VERSION 5.7 ;
BUSBITCHARS "[]" ;
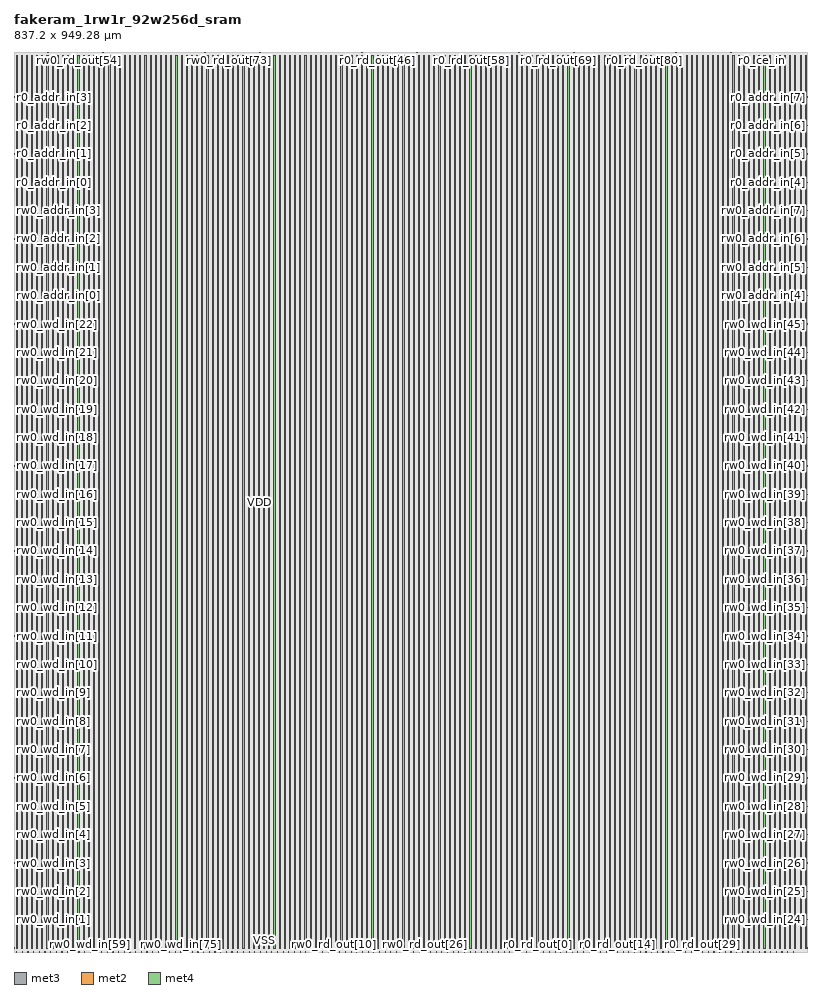
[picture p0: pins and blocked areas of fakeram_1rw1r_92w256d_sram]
MACRO fakeram_1rw1r_92w256d_sram
  FOREIGN fakeram_1rw1r_92w256d_sram 0 0 ;
  SYMMETRY X Y R90 ;
  SIZE 837.200 BY 949.280 ;
  CLASS BLOCK ;
  PIN rw0_wd_in[0]
    DIRECTION INPUT ;
    USE SIGNAL ;
    SHAPE ABUTMENT ;
    PORT
      LAYER met3 ;
      RECT 0.000 3.930 0.900 4.230 ;
    END
  END rw0_wd_in[0]
  PIN rw0_wd_in[1]
    DIRECTION INPUT ;
    USE SIGNAL ;
    SHAPE ABUTMENT ;
    PORT
      LAYER met3 ;
      RECT 0.000 33.850 0.900 34.150 ;
    END
  END rw0_wd_in[1]
  PIN rw0_wd_in[2]
    DIRECTION INPUT ;
    USE SIGNAL ;
    SHAPE ABUTMENT ;
    PORT
      LAYER met3 ;
      RECT 0.000 63.770 0.900 64.070 ;
    END
  END rw0_wd_in[2]
  PIN rw0_wd_in[3]
    DIRECTION INPUT ;
    USE SIGNAL ;
    SHAPE ABUTMENT ;
    PORT
      LAYER met3 ;
      RECT 0.000 93.690 0.900 93.990 ;
    END
  END rw0_wd_in[3]
  PIN rw0_wd_in[4]
    DIRECTION INPUT ;
    USE SIGNAL ;
    SHAPE ABUTMENT ;
    PORT
      LAYER met3 ;
      RECT 0.000 123.610 0.900 123.910 ;
    END
  END rw0_wd_in[4]
  PIN rw0_wd_in[5]
    DIRECTION INPUT ;
    USE SIGNAL ;
    SHAPE ABUTMENT ;
    PORT
      LAYER met3 ;
      RECT 0.000 153.530 0.900 153.830 ;
    END
  END rw0_wd_in[5]
  PIN rw0_wd_in[6]
    DIRECTION INPUT ;
    USE SIGNAL ;
    SHAPE ABUTMENT ;
    PORT
      LAYER met3 ;
      RECT 0.000 183.450 0.900 183.750 ;
    END
  END rw0_wd_in[6]
  PIN rw0_wd_in[7]
    DIRECTION INPUT ;
    USE SIGNAL ;
    SHAPE ABUTMENT ;
    PORT
      LAYER met3 ;
      RECT 0.000 213.370 0.900 213.670 ;
    END
  END rw0_wd_in[7]
  PIN rw0_wd_in[8]
    DIRECTION INPUT ;
    USE SIGNAL ;
    SHAPE ABUTMENT ;
    PORT
      LAYER met3 ;
      RECT 0.000 243.290 0.900 243.590 ;
    END
  END rw0_wd_in[8]
  PIN rw0_wd_in[9]
    DIRECTION INPUT ;
    USE SIGNAL ;
    SHAPE ABUTMENT ;
    PORT
      LAYER met3 ;
      RECT 0.000 273.210 0.900 273.510 ;
    END
  END rw0_wd_in[9]
  PIN rw0_wd_in[10]
    DIRECTION INPUT ;
    USE SIGNAL ;
    SHAPE ABUTMENT ;
    PORT
      LAYER met3 ;
      RECT 0.000 303.130 0.900 303.430 ;
    END
  END rw0_wd_in[10]
  PIN rw0_wd_in[11]
    DIRECTION INPUT ;
    USE SIGNAL ;
    SHAPE ABUTMENT ;
    PORT
      LAYER met3 ;
      RECT 0.000 333.050 0.900 333.350 ;
    END
  END rw0_wd_in[11]
  PIN rw0_wd_in[12]
    DIRECTION INPUT ;
    USE SIGNAL ;
    SHAPE ABUTMENT ;
    PORT
      LAYER met3 ;
      RECT 0.000 362.970 0.900 363.270 ;
    END
  END rw0_wd_in[12]
  PIN rw0_wd_in[13]
    DIRECTION INPUT ;
    USE SIGNAL ;
    SHAPE ABUTMENT ;
    PORT
      LAYER met3 ;
      RECT 0.000 392.890 0.900 393.190 ;
    END
  END rw0_wd_in[13]
  PIN rw0_wd_in[14]
    DIRECTION INPUT ;
    USE SIGNAL ;
    SHAPE ABUTMENT ;
    PORT
      LAYER met3 ;
      RECT 0.000 422.810 0.900 423.110 ;
    END
  END rw0_wd_in[14]
  PIN rw0_wd_in[15]
    DIRECTION INPUT ;
    USE SIGNAL ;
    SHAPE ABUTMENT ;
    PORT
      LAYER met3 ;
      RECT 0.000 452.730 0.900 453.030 ;
    END
  END rw0_wd_in[15]
  PIN rw0_wd_in[16]
    DIRECTION INPUT ;
    USE SIGNAL ;
    SHAPE ABUTMENT ;
    PORT
      LAYER met3 ;
      RECT 0.000 482.650 0.900 482.950 ;
    END
  END rw0_wd_in[16]
  PIN rw0_wd_in[17]
    DIRECTION INPUT ;
    USE SIGNAL ;
    SHAPE ABUTMENT ;
    PORT
      LAYER met3 ;
      RECT 0.000 512.570 0.900 512.870 ;
    END
  END rw0_wd_in[17]
  PIN rw0_wd_in[18]
    DIRECTION INPUT ;
    USE SIGNAL ;
    SHAPE ABUTMENT ;
    PORT
      LAYER met3 ;
      RECT 0.000 542.490 0.900 542.790 ;
    END
  END rw0_wd_in[18]
  PIN rw0_wd_in[19]
    DIRECTION INPUT ;
    USE SIGNAL ;
    SHAPE ABUTMENT ;
    PORT
      LAYER met3 ;
      RECT 0.000 572.410 0.900 572.710 ;
    END
  END rw0_wd_in[19]
  PIN rw0_wd_in[20]
    DIRECTION INPUT ;
    USE SIGNAL ;
    SHAPE ABUTMENT ;
    PORT
      LAYER met3 ;
      RECT 0.000 602.330 0.900 602.630 ;
    END
  END rw0_wd_in[20]
  PIN rw0_wd_in[21]
    DIRECTION INPUT ;
    USE SIGNAL ;
    SHAPE ABUTMENT ;
    PORT
      LAYER met3 ;
      RECT 0.000 632.250 0.900 632.550 ;
    END
  END rw0_wd_in[21]
  PIN rw0_wd_in[22]
    DIRECTION INPUT ;
    USE SIGNAL ;
    SHAPE ABUTMENT ;
    PORT
      LAYER met3 ;
      RECT 0.000 662.170 0.900 662.470 ;
    END
  END rw0_wd_in[22]
  PIN rw0_wd_in[23]
    DIRECTION INPUT ;
    USE SIGNAL ;
    SHAPE ABUTMENT ;
    PORT
      LAYER met3 ;
      RECT 836.300 3.930 837.200 4.230 ;
    END
  END rw0_wd_in[23]
  PIN rw0_wd_in[24]
    DIRECTION INPUT ;
    USE SIGNAL ;
    SHAPE ABUTMENT ;
    PORT
      LAYER met3 ;
      RECT 836.300 33.850 837.200 34.150 ;
    END
  END rw0_wd_in[24]
  PIN rw0_wd_in[25]
    DIRECTION INPUT ;
    USE SIGNAL ;
    SHAPE ABUTMENT ;
    PORT
      LAYER met3 ;
      RECT 836.300 63.770 837.200 64.070 ;
    END
  END rw0_wd_in[25]
  PIN rw0_wd_in[26]
    DIRECTION INPUT ;
    USE SIGNAL ;
    SHAPE ABUTMENT ;
    PORT
      LAYER met3 ;
      RECT 836.300 93.690 837.200 93.990 ;
    END
  END rw0_wd_in[26]
  PIN rw0_wd_in[27]
    DIRECTION INPUT ;
    USE SIGNAL ;
    SHAPE ABUTMENT ;
    PORT
      LAYER met3 ;
      RECT 836.300 123.610 837.200 123.910 ;
    END
  END rw0_wd_in[27]
  PIN rw0_wd_in[28]
    DIRECTION INPUT ;
    USE SIGNAL ;
    SHAPE ABUTMENT ;
    PORT
      LAYER met3 ;
      RECT 836.300 153.530 837.200 153.830 ;
    END
  END rw0_wd_in[28]
  PIN rw0_wd_in[29]
    DIRECTION INPUT ;
    USE SIGNAL ;
    SHAPE ABUTMENT ;
    PORT
      LAYER met3 ;
      RECT 836.300 183.450 837.200 183.750 ;
    END
  END rw0_wd_in[29]
  PIN rw0_wd_in[30]
    DIRECTION INPUT ;
    USE SIGNAL ;
    SHAPE ABUTMENT ;
    PORT
      LAYER met3 ;
      RECT 836.300 213.370 837.200 213.670 ;
    END
  END rw0_wd_in[30]
  PIN rw0_wd_in[31]
    DIRECTION INPUT ;
    USE SIGNAL ;
    SHAPE ABUTMENT ;
    PORT
      LAYER met3 ;
      RECT 836.300 243.290 837.200 243.590 ;
    END
  END rw0_wd_in[31]
  PIN rw0_wd_in[32]
    DIRECTION INPUT ;
    USE SIGNAL ;
    SHAPE ABUTMENT ;
    PORT
      LAYER met3 ;
      RECT 836.300 273.210 837.200 273.510 ;
    END
  END rw0_wd_in[32]
  PIN rw0_wd_in[33]
    DIRECTION INPUT ;
    USE SIGNAL ;
    SHAPE ABUTMENT ;
    PORT
      LAYER met3 ;
      RECT 836.300 303.130 837.200 303.430 ;
    END
  END rw0_wd_in[33]
  PIN rw0_wd_in[34]
    DIRECTION INPUT ;
    USE SIGNAL ;
    SHAPE ABUTMENT ;
    PORT
      LAYER met3 ;
      RECT 836.300 333.050 837.200 333.350 ;
    END
  END rw0_wd_in[34]
  PIN rw0_wd_in[35]
    DIRECTION INPUT ;
    USE SIGNAL ;
    SHAPE ABUTMENT ;
    PORT
      LAYER met3 ;
      RECT 836.300 362.970 837.200 363.270 ;
    END
  END rw0_wd_in[35]
  PIN rw0_wd_in[36]
    DIRECTION INPUT ;
    USE SIGNAL ;
    SHAPE ABUTMENT ;
    PORT
      LAYER met3 ;
      RECT 836.300 392.890 837.200 393.190 ;
    END
  END rw0_wd_in[36]
  PIN rw0_wd_in[37]
    DIRECTION INPUT ;
    USE SIGNAL ;
    SHAPE ABUTMENT ;
    PORT
      LAYER met3 ;
      RECT 836.300 422.810 837.200 423.110 ;
    END
  END rw0_wd_in[37]
  PIN rw0_wd_in[38]
    DIRECTION INPUT ;
    USE SIGNAL ;
    SHAPE ABUTMENT ;
    PORT
      LAYER met3 ;
      RECT 836.300 452.730 837.200 453.030 ;
    END
  END rw0_wd_in[38]
  PIN rw0_wd_in[39]
    DIRECTION INPUT ;
    USE SIGNAL ;
    SHAPE ABUTMENT ;
    PORT
      LAYER met3 ;
      RECT 836.300 482.650 837.200 482.950 ;
    END
  END rw0_wd_in[39]
  PIN rw0_wd_in[40]
    DIRECTION INPUT ;
    USE SIGNAL ;
    SHAPE ABUTMENT ;
    PORT
      LAYER met3 ;
      RECT 836.300 512.570 837.200 512.870 ;
    END
  END rw0_wd_in[40]
  PIN rw0_wd_in[41]
    DIRECTION INPUT ;
    USE SIGNAL ;
    SHAPE ABUTMENT ;
    PORT
      LAYER met3 ;
      RECT 836.300 542.490 837.200 542.790 ;
    END
  END rw0_wd_in[41]
  PIN rw0_wd_in[42]
    DIRECTION INPUT ;
    USE SIGNAL ;
    SHAPE ABUTMENT ;
    PORT
      LAYER met3 ;
      RECT 836.300 572.410 837.200 572.710 ;
    END
  END rw0_wd_in[42]
  PIN rw0_wd_in[43]
    DIRECTION INPUT ;
    USE SIGNAL ;
    SHAPE ABUTMENT ;
    PORT
      LAYER met3 ;
      RECT 836.300 602.330 837.200 602.630 ;
    END
  END rw0_wd_in[43]
  PIN rw0_wd_in[44]
    DIRECTION INPUT ;
    USE SIGNAL ;
    SHAPE ABUTMENT ;
    PORT
      LAYER met3 ;
      RECT 836.300 632.250 837.200 632.550 ;
    END
  END rw0_wd_in[44]
  PIN rw0_wd_in[45]
    DIRECTION INPUT ;
    USE SIGNAL ;
    SHAPE ABUTMENT ;
    PORT
      LAYER met3 ;
      RECT 836.300 662.170 837.200 662.470 ;
    END
  END rw0_wd_in[45]
  PIN rw0_wd_in[46]
    DIRECTION INPUT ;
    USE SIGNAL ;
    SHAPE ABUTMENT ;
    PORT
      LAYER met2 ;
      RECT 2.690 0.000 2.830 0.420 ;
    END
  END rw0_wd_in[46]
  PIN rw0_wd_in[47]
    DIRECTION INPUT ;
    USE SIGNAL ;
    SHAPE ABUTMENT ;
    PORT
      LAYER met2 ;
      RECT 8.670 0.000 8.810 0.420 ;
    END
  END rw0_wd_in[47]
  PIN rw0_wd_in[48]
    DIRECTION INPUT ;
    USE SIGNAL ;
    SHAPE ABUTMENT ;
    PORT
      LAYER met2 ;
      RECT 14.650 0.000 14.790 0.420 ;
    END
  END rw0_wd_in[48]
  PIN rw0_wd_in[49]
    DIRECTION INPUT ;
    USE SIGNAL ;
    SHAPE ABUTMENT ;
    PORT
      LAYER met2 ;
      RECT 20.630 0.000 20.770 0.420 ;
    END
  END rw0_wd_in[49]
  PIN rw0_wd_in[50]
    DIRECTION INPUT ;
    USE SIGNAL ;
    SHAPE ABUTMENT ;
    PORT
      LAYER met2 ;
      RECT 26.610 0.000 26.750 0.420 ;
    END
  END rw0_wd_in[50]
  PIN rw0_wd_in[51]
    DIRECTION INPUT ;
    USE SIGNAL ;
    SHAPE ABUTMENT ;
    PORT
      LAYER met2 ;
      RECT 32.590 0.000 32.730 0.420 ;
    END
  END rw0_wd_in[51]
  PIN rw0_wd_in[52]
    DIRECTION INPUT ;
    USE SIGNAL ;
    SHAPE ABUTMENT ;
    PORT
      LAYER met2 ;
      RECT 38.570 0.000 38.710 0.420 ;
    END
  END rw0_wd_in[52]
  PIN rw0_wd_in[53]
    DIRECTION INPUT ;
    USE SIGNAL ;
    SHAPE ABUTMENT ;
    PORT
      LAYER met2 ;
      RECT 44.550 0.000 44.690 0.420 ;
    END
  END rw0_wd_in[53]
  PIN rw0_wd_in[54]
    DIRECTION INPUT ;
    USE SIGNAL ;
    SHAPE ABUTMENT ;
    PORT
      LAYER met2 ;
      RECT 50.530 0.000 50.670 0.420 ;
    END
  END rw0_wd_in[54]
  PIN rw0_wd_in[55]
    DIRECTION INPUT ;
    USE SIGNAL ;
    SHAPE ABUTMENT ;
    PORT
      LAYER met2 ;
      RECT 56.510 0.000 56.650 0.420 ;
    END
  END rw0_wd_in[55]
  PIN rw0_wd_in[56]
    DIRECTION INPUT ;
    USE SIGNAL ;
    SHAPE ABUTMENT ;
    PORT
      LAYER met2 ;
      RECT 62.490 0.000 62.630 0.420 ;
    END
  END rw0_wd_in[56]
  PIN rw0_wd_in[57]
    DIRECTION INPUT ;
    USE SIGNAL ;
    SHAPE ABUTMENT ;
    PORT
      LAYER met2 ;
      RECT 68.470 0.000 68.610 0.420 ;
    END
  END rw0_wd_in[57]
  PIN rw0_wd_in[58]
    DIRECTION INPUT ;
    USE SIGNAL ;
    SHAPE ABUTMENT ;
    PORT
      LAYER met2 ;
      RECT 74.450 0.000 74.590 0.420 ;
    END
  END rw0_wd_in[58]
  PIN rw0_wd_in[59]
    DIRECTION INPUT ;
    USE SIGNAL ;
    SHAPE ABUTMENT ;
    PORT
      LAYER met2 ;
      RECT 80.430 0.000 80.570 0.420 ;
    END
  END rw0_wd_in[59]
  PIN rw0_wd_in[60]
    DIRECTION INPUT ;
    USE SIGNAL ;
    SHAPE ABUTMENT ;
    PORT
      LAYER met2 ;
      RECT 86.410 0.000 86.550 0.420 ;
    END
  END rw0_wd_in[60]
  PIN rw0_wd_in[61]
    DIRECTION INPUT ;
    USE SIGNAL ;
    SHAPE ABUTMENT ;
    PORT
      LAYER met2 ;
      RECT 92.390 0.000 92.530 0.420 ;
    END
  END rw0_wd_in[61]
  PIN rw0_wd_in[62]
    DIRECTION INPUT ;
    USE SIGNAL ;
    SHAPE ABUTMENT ;
    PORT
      LAYER met2 ;
      RECT 98.370 0.000 98.510 0.420 ;
    END
  END rw0_wd_in[62]
  PIN rw0_wd_in[63]
    DIRECTION INPUT ;
    USE SIGNAL ;
    SHAPE ABUTMENT ;
    PORT
      LAYER met2 ;
      RECT 104.350 0.000 104.490 0.420 ;
    END
  END rw0_wd_in[63]
  PIN rw0_wd_in[64]
    DIRECTION INPUT ;
    USE SIGNAL ;
    SHAPE ABUTMENT ;
    PORT
      LAYER met2 ;
      RECT 110.330 0.000 110.470 0.420 ;
    END
  END rw0_wd_in[64]
  PIN rw0_wd_in[65]
    DIRECTION INPUT ;
    USE SIGNAL ;
    SHAPE ABUTMENT ;
    PORT
      LAYER met2 ;
      RECT 116.310 0.000 116.450 0.420 ;
    END
  END rw0_wd_in[65]
  PIN rw0_wd_in[66]
    DIRECTION INPUT ;
    USE SIGNAL ;
    SHAPE ABUTMENT ;
    PORT
      LAYER met2 ;
      RECT 122.290 0.000 122.430 0.420 ;
    END
  END rw0_wd_in[66]
  PIN rw0_wd_in[67]
    DIRECTION INPUT ;
    USE SIGNAL ;
    SHAPE ABUTMENT ;
    PORT
      LAYER met2 ;
      RECT 128.270 0.000 128.410 0.420 ;
    END
  END rw0_wd_in[67]
  PIN rw0_wd_in[68]
    DIRECTION INPUT ;
    USE SIGNAL ;
    SHAPE ABUTMENT ;
    PORT
      LAYER met2 ;
      RECT 134.250 0.000 134.390 0.420 ;
    END
  END rw0_wd_in[68]
  PIN rw0_wd_in[69]
    DIRECTION INPUT ;
    USE SIGNAL ;
    SHAPE ABUTMENT ;
    PORT
      LAYER met2 ;
      RECT 140.230 0.000 140.370 0.420 ;
    END
  END rw0_wd_in[69]
  PIN rw0_wd_in[70]
    DIRECTION INPUT ;
    USE SIGNAL ;
    SHAPE ABUTMENT ;
    PORT
      LAYER met2 ;
      RECT 146.210 0.000 146.350 0.420 ;
    END
  END rw0_wd_in[70]
  PIN rw0_wd_in[71]
    DIRECTION INPUT ;
    USE SIGNAL ;
    SHAPE ABUTMENT ;
    PORT
      LAYER met2 ;
      RECT 152.190 0.000 152.330 0.420 ;
    END
  END rw0_wd_in[71]
  PIN rw0_wd_in[72]
    DIRECTION INPUT ;
    USE SIGNAL ;
    SHAPE ABUTMENT ;
    PORT
      LAYER met2 ;
      RECT 158.170 0.000 158.310 0.420 ;
    END
  END rw0_wd_in[72]
  PIN rw0_wd_in[73]
    DIRECTION INPUT ;
    USE SIGNAL ;
    SHAPE ABUTMENT ;
    PORT
      LAYER met2 ;
      RECT 164.150 0.000 164.290 0.420 ;
    END
  END rw0_wd_in[73]
  PIN rw0_wd_in[74]
    DIRECTION INPUT ;
    USE SIGNAL ;
    SHAPE ABUTMENT ;
    PORT
      LAYER met2 ;
      RECT 170.130 0.000 170.270 0.420 ;
    END
  END rw0_wd_in[74]
  PIN rw0_wd_in[75]
    DIRECTION INPUT ;
    USE SIGNAL ;
    SHAPE ABUTMENT ;
    PORT
      LAYER met2 ;
      RECT 176.110 0.000 176.250 0.420 ;
    END
  END rw0_wd_in[75]
  PIN rw0_wd_in[76]
    DIRECTION INPUT ;
    USE SIGNAL ;
    SHAPE ABUTMENT ;
    PORT
      LAYER met2 ;
      RECT 182.090 0.000 182.230 0.420 ;
    END
  END rw0_wd_in[76]
  PIN rw0_wd_in[77]
    DIRECTION INPUT ;
    USE SIGNAL ;
    SHAPE ABUTMENT ;
    PORT
      LAYER met2 ;
      RECT 188.070 0.000 188.210 0.420 ;
    END
  END rw0_wd_in[77]
  PIN rw0_wd_in[78]
    DIRECTION INPUT ;
    USE SIGNAL ;
    SHAPE ABUTMENT ;
    PORT
      LAYER met2 ;
      RECT 194.050 0.000 194.190 0.420 ;
    END
  END rw0_wd_in[78]
  PIN rw0_wd_in[79]
    DIRECTION INPUT ;
    USE SIGNAL ;
    SHAPE ABUTMENT ;
    PORT
      LAYER met2 ;
      RECT 200.030 0.000 200.170 0.420 ;
    END
  END rw0_wd_in[79]
  PIN rw0_wd_in[80]
    DIRECTION INPUT ;
    USE SIGNAL ;
    SHAPE ABUTMENT ;
    PORT
      LAYER met2 ;
      RECT 206.010 0.000 206.150 0.420 ;
    END
  END rw0_wd_in[80]
  PIN rw0_wd_in[81]
    DIRECTION INPUT ;
    USE SIGNAL ;
    SHAPE ABUTMENT ;
    PORT
      LAYER met2 ;
      RECT 211.990 0.000 212.130 0.420 ;
    END
  END rw0_wd_in[81]
  PIN rw0_wd_in[82]
    DIRECTION INPUT ;
    USE SIGNAL ;
    SHAPE ABUTMENT ;
    PORT
      LAYER met2 ;
      RECT 217.970 0.000 218.110 0.420 ;
    END
  END rw0_wd_in[82]
  PIN rw0_wd_in[83]
    DIRECTION INPUT ;
    USE SIGNAL ;
    SHAPE ABUTMENT ;
    PORT
      LAYER met2 ;
      RECT 223.950 0.000 224.090 0.420 ;
    END
  END rw0_wd_in[83]
  PIN rw0_wd_in[84]
    DIRECTION INPUT ;
    USE SIGNAL ;
    SHAPE ABUTMENT ;
    PORT
      LAYER met2 ;
      RECT 229.930 0.000 230.070 0.420 ;
    END
  END rw0_wd_in[84]
  PIN rw0_wd_in[85]
    DIRECTION INPUT ;
    USE SIGNAL ;
    SHAPE ABUTMENT ;
    PORT
      LAYER met2 ;
      RECT 235.910 0.000 236.050 0.420 ;
    END
  END rw0_wd_in[85]
  PIN rw0_wd_in[86]
    DIRECTION INPUT ;
    USE SIGNAL ;
    SHAPE ABUTMENT ;
    PORT
      LAYER met2 ;
      RECT 241.890 0.000 242.030 0.420 ;
    END
  END rw0_wd_in[86]
  PIN rw0_wd_in[87]
    DIRECTION INPUT ;
    USE SIGNAL ;
    SHAPE ABUTMENT ;
    PORT
      LAYER met2 ;
      RECT 247.870 0.000 248.010 0.420 ;
    END
  END rw0_wd_in[87]
  PIN rw0_wd_in[88]
    DIRECTION INPUT ;
    USE SIGNAL ;
    SHAPE ABUTMENT ;
    PORT
      LAYER met2 ;
      RECT 253.850 0.000 253.990 0.420 ;
    END
  END rw0_wd_in[88]
  PIN rw0_wd_in[89]
    DIRECTION INPUT ;
    USE SIGNAL ;
    SHAPE ABUTMENT ;
    PORT
      LAYER met2 ;
      RECT 259.830 0.000 259.970 0.420 ;
    END
  END rw0_wd_in[89]
  PIN rw0_wd_in[90]
    DIRECTION INPUT ;
    USE SIGNAL ;
    SHAPE ABUTMENT ;
    PORT
      LAYER met2 ;
      RECT 265.810 0.000 265.950 0.420 ;
    END
  END rw0_wd_in[90]
  PIN rw0_wd_in[91]
    DIRECTION INPUT ;
    USE SIGNAL ;
    SHAPE ABUTMENT ;
    PORT
      LAYER met2 ;
      RECT 271.790 0.000 271.930 0.420 ;
    END
  END rw0_wd_in[91]
  PIN rw0_rd_out[0]
    DIRECTION OUTPUT ;
    USE SIGNAL ;
    SHAPE ABUTMENT ;
    PORT
      LAYER met2 ;
      RECT 277.770 0.000 277.910 0.420 ;
    END
  END rw0_rd_out[0]
  PIN rw0_rd_out[1]
    DIRECTION OUTPUT ;
    USE SIGNAL ;
    SHAPE ABUTMENT ;
    PORT
      LAYER met2 ;
      RECT 283.750 0.000 283.890 0.420 ;
    END
  END rw0_rd_out[1]
  PIN rw0_rd_out[2]
    DIRECTION OUTPUT ;
    USE SIGNAL ;
    SHAPE ABUTMENT ;
    PORT
      LAYER met2 ;
      RECT 289.730 0.000 289.870 0.420 ;
    END
  END rw0_rd_out[2]
  PIN rw0_rd_out[3]
    DIRECTION OUTPUT ;
    USE SIGNAL ;
    SHAPE ABUTMENT ;
    PORT
      LAYER met2 ;
      RECT 295.710 0.000 295.850 0.420 ;
    END
  END rw0_rd_out[3]
  PIN rw0_rd_out[4]
    DIRECTION OUTPUT ;
    USE SIGNAL ;
    SHAPE ABUTMENT ;
    PORT
      LAYER met2 ;
      RECT 301.690 0.000 301.830 0.420 ;
    END
  END rw0_rd_out[4]
  PIN rw0_rd_out[5]
    DIRECTION OUTPUT ;
    USE SIGNAL ;
    SHAPE ABUTMENT ;
    PORT
      LAYER met2 ;
      RECT 307.670 0.000 307.810 0.420 ;
    END
  END rw0_rd_out[5]
  PIN rw0_rd_out[6]
    DIRECTION OUTPUT ;
    USE SIGNAL ;
    SHAPE ABUTMENT ;
    PORT
      LAYER met2 ;
      RECT 313.650 0.000 313.790 0.420 ;
    END
  END rw0_rd_out[6]
  PIN rw0_rd_out[7]
    DIRECTION OUTPUT ;
    USE SIGNAL ;
    SHAPE ABUTMENT ;
    PORT
      LAYER met2 ;
      RECT 319.630 0.000 319.770 0.420 ;
    END
  END rw0_rd_out[7]
  PIN rw0_rd_out[8]
    DIRECTION OUTPUT ;
    USE SIGNAL ;
    SHAPE ABUTMENT ;
    PORT
      LAYER met2 ;
      RECT 325.610 0.000 325.750 0.420 ;
    END
  END rw0_rd_out[8]
  PIN rw0_rd_out[9]
    DIRECTION OUTPUT ;
    USE SIGNAL ;
    SHAPE ABUTMENT ;
    PORT
      LAYER met2 ;
      RECT 331.590 0.000 331.730 0.420 ;
    END
  END rw0_rd_out[9]
  PIN rw0_rd_out[10]
    DIRECTION OUTPUT ;
    USE SIGNAL ;
    SHAPE ABUTMENT ;
    PORT
      LAYER met2 ;
      RECT 337.570 0.000 337.710 0.420 ;
    END
  END rw0_rd_out[10]
  PIN rw0_rd_out[11]
    DIRECTION OUTPUT ;
    USE SIGNAL ;
    SHAPE ABUTMENT ;
    PORT
      LAYER met2 ;
      RECT 343.550 0.000 343.690 0.420 ;
    END
  END rw0_rd_out[11]
  PIN rw0_rd_out[12]
    DIRECTION OUTPUT ;
    USE SIGNAL ;
    SHAPE ABUTMENT ;
    PORT
      LAYER met2 ;
      RECT 349.530 0.000 349.670 0.420 ;
    END
  END rw0_rd_out[12]
  PIN rw0_rd_out[13]
    DIRECTION OUTPUT ;
    USE SIGNAL ;
    SHAPE ABUTMENT ;
    PORT
      LAYER met2 ;
      RECT 355.510 0.000 355.650 0.420 ;
    END
  END rw0_rd_out[13]
  PIN rw0_rd_out[14]
    DIRECTION OUTPUT ;
    USE SIGNAL ;
    SHAPE ABUTMENT ;
    PORT
      LAYER met2 ;
      RECT 361.490 0.000 361.630 0.420 ;
    END
  END rw0_rd_out[14]
  PIN rw0_rd_out[15]
    DIRECTION OUTPUT ;
    USE SIGNAL ;
    SHAPE ABUTMENT ;
    PORT
      LAYER met2 ;
      RECT 367.470 0.000 367.610 0.420 ;
    END
  END rw0_rd_out[15]
  PIN rw0_rd_out[16]
    DIRECTION OUTPUT ;
    USE SIGNAL ;
    SHAPE ABUTMENT ;
    PORT
      LAYER met2 ;
      RECT 373.450 0.000 373.590 0.420 ;
    END
  END rw0_rd_out[16]
  PIN rw0_rd_out[17]
    DIRECTION OUTPUT ;
    USE SIGNAL ;
    SHAPE ABUTMENT ;
    PORT
      LAYER met2 ;
      RECT 379.430 0.000 379.570 0.420 ;
    END
  END rw0_rd_out[17]
  PIN rw0_rd_out[18]
    DIRECTION OUTPUT ;
    USE SIGNAL ;
    SHAPE ABUTMENT ;
    PORT
      LAYER met2 ;
      RECT 385.410 0.000 385.550 0.420 ;
    END
  END rw0_rd_out[18]
  PIN rw0_rd_out[19]
    DIRECTION OUTPUT ;
    USE SIGNAL ;
    SHAPE ABUTMENT ;
    PORT
      LAYER met2 ;
      RECT 391.390 0.000 391.530 0.420 ;
    END
  END rw0_rd_out[19]
  PIN rw0_rd_out[20]
    DIRECTION OUTPUT ;
    USE SIGNAL ;
    SHAPE ABUTMENT ;
    PORT
      LAYER met2 ;
      RECT 397.370 0.000 397.510 0.420 ;
    END
  END rw0_rd_out[20]
  PIN rw0_rd_out[21]
    DIRECTION OUTPUT ;
    USE SIGNAL ;
    SHAPE ABUTMENT ;
    PORT
      LAYER met2 ;
      RECT 403.350 0.000 403.490 0.420 ;
    END
  END rw0_rd_out[21]
  PIN rw0_rd_out[22]
    DIRECTION OUTPUT ;
    USE SIGNAL ;
    SHAPE ABUTMENT ;
    PORT
      LAYER met2 ;
      RECT 409.330 0.000 409.470 0.420 ;
    END
  END rw0_rd_out[22]
  PIN rw0_rd_out[23]
    DIRECTION OUTPUT ;
    USE SIGNAL ;
    SHAPE ABUTMENT ;
    PORT
      LAYER met2 ;
      RECT 415.310 0.000 415.450 0.420 ;
    END
  END rw0_rd_out[23]
  PIN rw0_rd_out[24]
    DIRECTION OUTPUT ;
    USE SIGNAL ;
    SHAPE ABUTMENT ;
    PORT
      LAYER met2 ;
      RECT 421.290 0.000 421.430 0.420 ;
    END
  END rw0_rd_out[24]
  PIN rw0_rd_out[25]
    DIRECTION OUTPUT ;
    USE SIGNAL ;
    SHAPE ABUTMENT ;
    PORT
      LAYER met2 ;
      RECT 427.270 0.000 427.410 0.420 ;
    END
  END rw0_rd_out[25]
  PIN rw0_rd_out[26]
    DIRECTION OUTPUT ;
    USE SIGNAL ;
    SHAPE ABUTMENT ;
    PORT
      LAYER met2 ;
      RECT 433.250 0.000 433.390 0.420 ;
    END
  END rw0_rd_out[26]
  PIN rw0_rd_out[27]
    DIRECTION OUTPUT ;
    USE SIGNAL ;
    SHAPE ABUTMENT ;
    PORT
      LAYER met2 ;
      RECT 439.230 0.000 439.370 0.420 ;
    END
  END rw0_rd_out[27]
  PIN rw0_rd_out[28]
    DIRECTION OUTPUT ;
    USE SIGNAL ;
    SHAPE ABUTMENT ;
    PORT
      LAYER met2 ;
      RECT 445.210 0.000 445.350 0.420 ;
    END
  END rw0_rd_out[28]
  PIN rw0_rd_out[29]
    DIRECTION OUTPUT ;
    USE SIGNAL ;
    SHAPE ABUTMENT ;
    PORT
      LAYER met2 ;
      RECT 451.190 0.000 451.330 0.420 ;
    END
  END rw0_rd_out[29]
  PIN rw0_rd_out[30]
    DIRECTION OUTPUT ;
    USE SIGNAL ;
    SHAPE ABUTMENT ;
    PORT
      LAYER met2 ;
      RECT 457.170 0.000 457.310 0.420 ;
    END
  END rw0_rd_out[30]
  PIN rw0_rd_out[31]
    DIRECTION OUTPUT ;
    USE SIGNAL ;
    SHAPE ABUTMENT ;
    PORT
      LAYER met2 ;
      RECT 463.150 0.000 463.290 0.420 ;
    END
  END rw0_rd_out[31]
  PIN rw0_rd_out[32]
    DIRECTION OUTPUT ;
    USE SIGNAL ;
    SHAPE ABUTMENT ;
    PORT
      LAYER met2 ;
      RECT 469.130 0.000 469.270 0.420 ;
    END
  END rw0_rd_out[32]
  PIN rw0_rd_out[33]
    DIRECTION OUTPUT ;
    USE SIGNAL ;
    SHAPE ABUTMENT ;
    PORT
      LAYER met2 ;
      RECT 475.110 0.000 475.250 0.420 ;
    END
  END rw0_rd_out[33]
  PIN rw0_rd_out[34]
    DIRECTION OUTPUT ;
    USE SIGNAL ;
    SHAPE ABUTMENT ;
    PORT
      LAYER met2 ;
      RECT 481.090 0.000 481.230 0.420 ;
    END
  END rw0_rd_out[34]
  PIN rw0_rd_out[35]
    DIRECTION OUTPUT ;
    USE SIGNAL ;
    SHAPE ABUTMENT ;
    PORT
      LAYER met2 ;
      RECT 487.070 0.000 487.210 0.420 ;
    END
  END rw0_rd_out[35]
  PIN rw0_rd_out[36]
    DIRECTION OUTPUT ;
    USE SIGNAL ;
    SHAPE ABUTMENT ;
    PORT
      LAYER met2 ;
      RECT 493.050 0.000 493.190 0.420 ;
    END
  END rw0_rd_out[36]
  PIN rw0_rd_out[37]
    DIRECTION OUTPUT ;
    USE SIGNAL ;
    SHAPE ABUTMENT ;
    PORT
      LAYER met2 ;
      RECT 499.030 0.000 499.170 0.420 ;
    END
  END rw0_rd_out[37]
  PIN rw0_rd_out[38]
    DIRECTION OUTPUT ;
    USE SIGNAL ;
    SHAPE ABUTMENT ;
    PORT
      LAYER met2 ;
      RECT 505.010 0.000 505.150 0.420 ;
    END
  END rw0_rd_out[38]
  PIN rw0_rd_out[39]
    DIRECTION OUTPUT ;
    USE SIGNAL ;
    SHAPE ABUTMENT ;
    PORT
      LAYER met2 ;
      RECT 510.990 0.000 511.130 0.420 ;
    END
  END rw0_rd_out[39]
  PIN rw0_rd_out[40]
    DIRECTION OUTPUT ;
    USE SIGNAL ;
    SHAPE ABUTMENT ;
    PORT
      LAYER met2 ;
      RECT 516.970 0.000 517.110 0.420 ;
    END
  END rw0_rd_out[40]
  PIN rw0_rd_out[41]
    DIRECTION OUTPUT ;
    USE SIGNAL ;
    SHAPE ABUTMENT ;
    PORT
      LAYER met2 ;
      RECT 522.950 0.000 523.090 0.420 ;
    END
  END rw0_rd_out[41]
  PIN rw0_rd_out[42]
    DIRECTION OUTPUT ;
    USE SIGNAL ;
    SHAPE ABUTMENT ;
    PORT
      LAYER met2 ;
      RECT 528.930 0.000 529.070 0.420 ;
    END
  END rw0_rd_out[42]
  PIN rw0_rd_out[43]
    DIRECTION OUTPUT ;
    USE SIGNAL ;
    SHAPE ABUTMENT ;
    PORT
      LAYER met2 ;
      RECT 534.910 0.000 535.050 0.420 ;
    END
  END rw0_rd_out[43]
  PIN rw0_rd_out[44]
    DIRECTION OUTPUT ;
    USE SIGNAL ;
    SHAPE ABUTMENT ;
    PORT
      LAYER met2 ;
      RECT 540.890 0.000 541.030 0.420 ;
    END
  END rw0_rd_out[44]
  PIN rw0_rd_out[45]
    DIRECTION OUTPUT ;
    USE SIGNAL ;
    SHAPE ABUTMENT ;
    PORT
      LAYER met2 ;
      RECT 546.870 0.000 547.010 0.420 ;
    END
  END rw0_rd_out[45]
  PIN rw0_rd_out[46]
    DIRECTION OUTPUT ;
    USE SIGNAL ;
    SHAPE ABUTMENT ;
    PORT
      LAYER met2 ;
      RECT 2.690 948.860 2.830 949.280 ;
    END
  END rw0_rd_out[46]
  PIN rw0_rd_out[47]
    DIRECTION OUTPUT ;
    USE SIGNAL ;
    SHAPE ABUTMENT ;
    PORT
      LAYER met2 ;
      RECT 10.970 948.860 11.110 949.280 ;
    END
  END rw0_rd_out[47]
  PIN rw0_rd_out[48]
    DIRECTION OUTPUT ;
    USE SIGNAL ;
    SHAPE ABUTMENT ;
    PORT
      LAYER met2 ;
      RECT 19.250 948.860 19.390 949.280 ;
    END
  END rw0_rd_out[48]
  PIN rw0_rd_out[49]
    DIRECTION OUTPUT ;
    USE SIGNAL ;
    SHAPE ABUTMENT ;
    PORT
      LAYER met2 ;
      RECT 27.530 948.860 27.670 949.280 ;
    END
  END rw0_rd_out[49]
  PIN rw0_rd_out[50]
    DIRECTION OUTPUT ;
    USE SIGNAL ;
    SHAPE ABUTMENT ;
    PORT
      LAYER met2 ;
      RECT 35.810 948.860 35.950 949.280 ;
    END
  END rw0_rd_out[50]
  PIN rw0_rd_out[51]
    DIRECTION OUTPUT ;
    USE SIGNAL ;
    SHAPE ABUTMENT ;
    PORT
      LAYER met2 ;
      RECT 44.090 948.860 44.230 949.280 ;
    END
  END rw0_rd_out[51]
  PIN rw0_rd_out[52]
    DIRECTION OUTPUT ;
    USE SIGNAL ;
    SHAPE ABUTMENT ;
    PORT
      LAYER met2 ;
      RECT 52.370 948.860 52.510 949.280 ;
    END
  END rw0_rd_out[52]
  PIN rw0_rd_out[53]
    DIRECTION OUTPUT ;
    USE SIGNAL ;
    SHAPE ABUTMENT ;
    PORT
      LAYER met2 ;
      RECT 60.650 948.860 60.790 949.280 ;
    END
  END rw0_rd_out[53]
  PIN rw0_rd_out[54]
    DIRECTION OUTPUT ;
    USE SIGNAL ;
    SHAPE ABUTMENT ;
    PORT
      LAYER met2 ;
      RECT 68.930 948.860 69.070 949.280 ;
    END
  END rw0_rd_out[54]
  PIN rw0_rd_out[55]
    DIRECTION OUTPUT ;
    USE SIGNAL ;
    SHAPE ABUTMENT ;
    PORT
      LAYER met2 ;
      RECT 77.210 948.860 77.350 949.280 ;
    END
  END rw0_rd_out[55]
  PIN rw0_rd_out[56]
    DIRECTION OUTPUT ;
    USE SIGNAL ;
    SHAPE ABUTMENT ;
    PORT
      LAYER met2 ;
      RECT 85.490 948.860 85.630 949.280 ;
    END
  END rw0_rd_out[56]
  PIN rw0_rd_out[57]
    DIRECTION OUTPUT ;
    USE SIGNAL ;
    SHAPE ABUTMENT ;
    PORT
      LAYER met2 ;
      RECT 93.770 948.860 93.910 949.280 ;
    END
  END rw0_rd_out[57]
  PIN rw0_rd_out[58]
    DIRECTION OUTPUT ;
    USE SIGNAL ;
    SHAPE ABUTMENT ;
    PORT
      LAYER met2 ;
      RECT 102.050 948.860 102.190 949.280 ;
    END
  END rw0_rd_out[58]
  PIN rw0_rd_out[59]
    DIRECTION OUTPUT ;
    USE SIGNAL ;
    SHAPE ABUTMENT ;
    PORT
      LAYER met2 ;
      RECT 110.330 948.860 110.470 949.280 ;
    END
  END rw0_rd_out[59]
  PIN rw0_rd_out[60]
    DIRECTION OUTPUT ;
    USE SIGNAL ;
    SHAPE ABUTMENT ;
    PORT
      LAYER met2 ;
      RECT 118.610 948.860 118.750 949.280 ;
    END
  END rw0_rd_out[60]
  PIN rw0_rd_out[61]
    DIRECTION OUTPUT ;
    USE SIGNAL ;
    SHAPE ABUTMENT ;
    PORT
      LAYER met2 ;
      RECT 126.890 948.860 127.030 949.280 ;
    END
  END rw0_rd_out[61]
  PIN rw0_rd_out[62]
    DIRECTION OUTPUT ;
    USE SIGNAL ;
    SHAPE ABUTMENT ;
    PORT
      LAYER met2 ;
      RECT 135.170 948.860 135.310 949.280 ;
    END
  END rw0_rd_out[62]
  PIN rw0_rd_out[63]
    DIRECTION OUTPUT ;
    USE SIGNAL ;
    SHAPE ABUTMENT ;
    PORT
      LAYER met2 ;
      RECT 143.450 948.860 143.590 949.280 ;
    END
  END rw0_rd_out[63]
  PIN rw0_rd_out[64]
    DIRECTION OUTPUT ;
    USE SIGNAL ;
    SHAPE ABUTMENT ;
    PORT
      LAYER met2 ;
      RECT 151.730 948.860 151.870 949.280 ;
    END
  END rw0_rd_out[64]
  PIN rw0_rd_out[65]
    DIRECTION OUTPUT ;
    USE SIGNAL ;
    SHAPE ABUTMENT ;
    PORT
      LAYER met2 ;
      RECT 160.010 948.860 160.150 949.280 ;
    END
  END rw0_rd_out[65]
  PIN rw0_rd_out[66]
    DIRECTION OUTPUT ;
    USE SIGNAL ;
    SHAPE ABUTMENT ;
    PORT
      LAYER met2 ;
      RECT 168.290 948.860 168.430 949.280 ;
    END
  END rw0_rd_out[66]
  PIN rw0_rd_out[67]
    DIRECTION OUTPUT ;
    USE SIGNAL ;
    SHAPE ABUTMENT ;
    PORT
      LAYER met2 ;
      RECT 176.570 948.860 176.710 949.280 ;
    END
  END rw0_rd_out[67]
  PIN rw0_rd_out[68]
    DIRECTION OUTPUT ;
    USE SIGNAL ;
    SHAPE ABUTMENT ;
    PORT
      LAYER met2 ;
      RECT 184.850 948.860 184.990 949.280 ;
    END
  END rw0_rd_out[68]
  PIN rw0_rd_out[69]
    DIRECTION OUTPUT ;
    USE SIGNAL ;
    SHAPE ABUTMENT ;
    PORT
      LAYER met2 ;
      RECT 193.130 948.860 193.270 949.280 ;
    END
  END rw0_rd_out[69]
  PIN rw0_rd_out[70]
    DIRECTION OUTPUT ;
    USE SIGNAL ;
    SHAPE ABUTMENT ;
    PORT
      LAYER met2 ;
      RECT 201.410 948.860 201.550 949.280 ;
    END
  END rw0_rd_out[70]
  PIN rw0_rd_out[71]
    DIRECTION OUTPUT ;
    USE SIGNAL ;
    SHAPE ABUTMENT ;
    PORT
      LAYER met2 ;
      RECT 209.690 948.860 209.830 949.280 ;
    END
  END rw0_rd_out[71]
  PIN rw0_rd_out[72]
    DIRECTION OUTPUT ;
    USE SIGNAL ;
    SHAPE ABUTMENT ;
    PORT
      LAYER met2 ;
      RECT 217.970 948.860 218.110 949.280 ;
    END
  END rw0_rd_out[72]
  PIN rw0_rd_out[73]
    DIRECTION OUTPUT ;
    USE SIGNAL ;
    SHAPE ABUTMENT ;
    PORT
      LAYER met2 ;
      RECT 226.250 948.860 226.390 949.280 ;
    END
  END rw0_rd_out[73]
  PIN rw0_rd_out[74]
    DIRECTION OUTPUT ;
    USE SIGNAL ;
    SHAPE ABUTMENT ;
    PORT
      LAYER met2 ;
      RECT 234.530 948.860 234.670 949.280 ;
    END
  END rw0_rd_out[74]
  PIN rw0_rd_out[75]
    DIRECTION OUTPUT ;
    USE SIGNAL ;
    SHAPE ABUTMENT ;
    PORT
      LAYER met2 ;
      RECT 242.810 948.860 242.950 949.280 ;
    END
  END rw0_rd_out[75]
  PIN rw0_rd_out[76]
    DIRECTION OUTPUT ;
    USE SIGNAL ;
    SHAPE ABUTMENT ;
    PORT
      LAYER met2 ;
      RECT 251.090 948.860 251.230 949.280 ;
    END
  END rw0_rd_out[76]
  PIN rw0_rd_out[77]
    DIRECTION OUTPUT ;
    USE SIGNAL ;
    SHAPE ABUTMENT ;
    PORT
      LAYER met2 ;
      RECT 259.370 948.860 259.510 949.280 ;
    END
  END rw0_rd_out[77]
  PIN rw0_rd_out[78]
    DIRECTION OUTPUT ;
    USE SIGNAL ;
    SHAPE ABUTMENT ;
    PORT
      LAYER met2 ;
      RECT 267.650 948.860 267.790 949.280 ;
    END
  END rw0_rd_out[78]
  PIN rw0_rd_out[79]
    DIRECTION OUTPUT ;
    USE SIGNAL ;
    SHAPE ABUTMENT ;
    PORT
      LAYER met2 ;
      RECT 275.930 948.860 276.070 949.280 ;
    END
  END rw0_rd_out[79]
  PIN rw0_rd_out[80]
    DIRECTION OUTPUT ;
    USE SIGNAL ;
    SHAPE ABUTMENT ;
    PORT
      LAYER met2 ;
      RECT 284.210 948.860 284.350 949.280 ;
    END
  END rw0_rd_out[80]
  PIN rw0_rd_out[81]
    DIRECTION OUTPUT ;
    USE SIGNAL ;
    SHAPE ABUTMENT ;
    PORT
      LAYER met2 ;
      RECT 292.490 948.860 292.630 949.280 ;
    END
  END rw0_rd_out[81]
  PIN rw0_rd_out[82]
    DIRECTION OUTPUT ;
    USE SIGNAL ;
    SHAPE ABUTMENT ;
    PORT
      LAYER met2 ;
      RECT 300.770 948.860 300.910 949.280 ;
    END
  END rw0_rd_out[82]
  PIN rw0_rd_out[83]
    DIRECTION OUTPUT ;
    USE SIGNAL ;
    SHAPE ABUTMENT ;
    PORT
      LAYER met2 ;
      RECT 309.050 948.860 309.190 949.280 ;
    END
  END rw0_rd_out[83]
  PIN rw0_rd_out[84]
    DIRECTION OUTPUT ;
    USE SIGNAL ;
    SHAPE ABUTMENT ;
    PORT
      LAYER met2 ;
      RECT 317.330 948.860 317.470 949.280 ;
    END
  END rw0_rd_out[84]
  PIN rw0_rd_out[85]
    DIRECTION OUTPUT ;
    USE SIGNAL ;
    SHAPE ABUTMENT ;
    PORT
      LAYER met2 ;
      RECT 325.610 948.860 325.750 949.280 ;
    END
  END rw0_rd_out[85]
  PIN rw0_rd_out[86]
    DIRECTION OUTPUT ;
    USE SIGNAL ;
    SHAPE ABUTMENT ;
    PORT
      LAYER met2 ;
      RECT 333.890 948.860 334.030 949.280 ;
    END
  END rw0_rd_out[86]
  PIN rw0_rd_out[87]
    DIRECTION OUTPUT ;
    USE SIGNAL ;
    SHAPE ABUTMENT ;
    PORT
      LAYER met2 ;
      RECT 342.170 948.860 342.310 949.280 ;
    END
  END rw0_rd_out[87]
  PIN rw0_rd_out[88]
    DIRECTION OUTPUT ;
    USE SIGNAL ;
    SHAPE ABUTMENT ;
    PORT
      LAYER met2 ;
      RECT 350.450 948.860 350.590 949.280 ;
    END
  END rw0_rd_out[88]
  PIN rw0_rd_out[89]
    DIRECTION OUTPUT ;
    USE SIGNAL ;
    SHAPE ABUTMENT ;
    PORT
      LAYER met2 ;
      RECT 358.730 948.860 358.870 949.280 ;
    END
  END rw0_rd_out[89]
  PIN rw0_rd_out[90]
    DIRECTION OUTPUT ;
    USE SIGNAL ;
    SHAPE ABUTMENT ;
    PORT
      LAYER met2 ;
      RECT 367.010 948.860 367.150 949.280 ;
    END
  END rw0_rd_out[90]
  PIN rw0_rd_out[91]
    DIRECTION OUTPUT ;
    USE SIGNAL ;
    SHAPE ABUTMENT ;
    PORT
      LAYER met2 ;
      RECT 375.290 948.860 375.430 949.280 ;
    END
  END rw0_rd_out[91]
  PIN r0_rd_out[0]
    DIRECTION OUTPUT ;
    USE SIGNAL ;
    SHAPE ABUTMENT ;
    PORT
      LAYER met2 ;
      RECT 552.850 0.000 552.990 0.420 ;
    END
  END r0_rd_out[0]
  PIN r0_rd_out[1]
    DIRECTION OUTPUT ;
    USE SIGNAL ;
    SHAPE ABUTMENT ;
    PORT
      LAYER met2 ;
      RECT 558.830 0.000 558.970 0.420 ;
    END
  END r0_rd_out[1]
  PIN r0_rd_out[2]
    DIRECTION OUTPUT ;
    USE SIGNAL ;
    SHAPE ABUTMENT ;
    PORT
      LAYER met2 ;
      RECT 564.810 0.000 564.950 0.420 ;
    END
  END r0_rd_out[2]
  PIN r0_rd_out[3]
    DIRECTION OUTPUT ;
    USE SIGNAL ;
    SHAPE ABUTMENT ;
    PORT
      LAYER met2 ;
      RECT 570.790 0.000 570.930 0.420 ;
    END
  END r0_rd_out[3]
  PIN r0_rd_out[4]
    DIRECTION OUTPUT ;
    USE SIGNAL ;
    SHAPE ABUTMENT ;
    PORT
      LAYER met2 ;
      RECT 576.770 0.000 576.910 0.420 ;
    END
  END r0_rd_out[4]
  PIN r0_rd_out[5]
    DIRECTION OUTPUT ;
    USE SIGNAL ;
    SHAPE ABUTMENT ;
    PORT
      LAYER met2 ;
      RECT 582.750 0.000 582.890 0.420 ;
    END
  END r0_rd_out[5]
  PIN r0_rd_out[6]
    DIRECTION OUTPUT ;
    USE SIGNAL ;
    SHAPE ABUTMENT ;
    PORT
      LAYER met2 ;
      RECT 588.730 0.000 588.870 0.420 ;
    END
  END r0_rd_out[6]
  PIN r0_rd_out[7]
    DIRECTION OUTPUT ;
    USE SIGNAL ;
    SHAPE ABUTMENT ;
    PORT
      LAYER met2 ;
      RECT 594.710 0.000 594.850 0.420 ;
    END
  END r0_rd_out[7]
  PIN r0_rd_out[8]
    DIRECTION OUTPUT ;
    USE SIGNAL ;
    SHAPE ABUTMENT ;
    PORT
      LAYER met2 ;
      RECT 600.690 0.000 600.830 0.420 ;
    END
  END r0_rd_out[8]
  PIN r0_rd_out[9]
    DIRECTION OUTPUT ;
    USE SIGNAL ;
    SHAPE ABUTMENT ;
    PORT
      LAYER met2 ;
      RECT 606.670 0.000 606.810 0.420 ;
    END
  END r0_rd_out[9]
  PIN r0_rd_out[10]
    DIRECTION OUTPUT ;
    USE SIGNAL ;
    SHAPE ABUTMENT ;
    PORT
      LAYER met2 ;
      RECT 612.650 0.000 612.790 0.420 ;
    END
  END r0_rd_out[10]
  PIN r0_rd_out[11]
    DIRECTION OUTPUT ;
    USE SIGNAL ;
    SHAPE ABUTMENT ;
    PORT
      LAYER met2 ;
      RECT 618.630 0.000 618.770 0.420 ;
    END
  END r0_rd_out[11]
  PIN r0_rd_out[12]
    DIRECTION OUTPUT ;
    USE SIGNAL ;
    SHAPE ABUTMENT ;
    PORT
      LAYER met2 ;
      RECT 624.610 0.000 624.750 0.420 ;
    END
  END r0_rd_out[12]
  PIN r0_rd_out[13]
    DIRECTION OUTPUT ;
    USE SIGNAL ;
    SHAPE ABUTMENT ;
    PORT
      LAYER met2 ;
      RECT 630.590 0.000 630.730 0.420 ;
    END
  END r0_rd_out[13]
  PIN r0_rd_out[14]
    DIRECTION OUTPUT ;
    USE SIGNAL ;
    SHAPE ABUTMENT ;
    PORT
      LAYER met2 ;
      RECT 636.570 0.000 636.710 0.420 ;
    END
  END r0_rd_out[14]
  PIN r0_rd_out[15]
    DIRECTION OUTPUT ;
    USE SIGNAL ;
    SHAPE ABUTMENT ;
    PORT
      LAYER met2 ;
      RECT 642.550 0.000 642.690 0.420 ;
    END
  END r0_rd_out[15]
  PIN r0_rd_out[16]
    DIRECTION OUTPUT ;
    USE SIGNAL ;
    SHAPE ABUTMENT ;
    PORT
      LAYER met2 ;
      RECT 648.530 0.000 648.670 0.420 ;
    END
  END r0_rd_out[16]
  PIN r0_rd_out[17]
    DIRECTION OUTPUT ;
    USE SIGNAL ;
    SHAPE ABUTMENT ;
    PORT
      LAYER met2 ;
      RECT 654.510 0.000 654.650 0.420 ;
    END
  END r0_rd_out[17]
  PIN r0_rd_out[18]
    DIRECTION OUTPUT ;
    USE SIGNAL ;
    SHAPE ABUTMENT ;
    PORT
      LAYER met2 ;
      RECT 660.490 0.000 660.630 0.420 ;
    END
  END r0_rd_out[18]
  PIN r0_rd_out[19]
    DIRECTION OUTPUT ;
    USE SIGNAL ;
    SHAPE ABUTMENT ;
    PORT
      LAYER met2 ;
      RECT 666.470 0.000 666.610 0.420 ;
    END
  END r0_rd_out[19]
  PIN r0_rd_out[20]
    DIRECTION OUTPUT ;
    USE SIGNAL ;
    SHAPE ABUTMENT ;
    PORT
      LAYER met2 ;
      RECT 672.450 0.000 672.590 0.420 ;
    END
  END r0_rd_out[20]
  PIN r0_rd_out[21]
    DIRECTION OUTPUT ;
    USE SIGNAL ;
    SHAPE ABUTMENT ;
    PORT
      LAYER met2 ;
      RECT 678.430 0.000 678.570 0.420 ;
    END
  END r0_rd_out[21]
  PIN r0_rd_out[22]
    DIRECTION OUTPUT ;
    USE SIGNAL ;
    SHAPE ABUTMENT ;
    PORT
      LAYER met2 ;
      RECT 684.410 0.000 684.550 0.420 ;
    END
  END r0_rd_out[22]
  PIN r0_rd_out[23]
    DIRECTION OUTPUT ;
    USE SIGNAL ;
    SHAPE ABUTMENT ;
    PORT
      LAYER met2 ;
      RECT 690.390 0.000 690.530 0.420 ;
    END
  END r0_rd_out[23]
  PIN r0_rd_out[24]
    DIRECTION OUTPUT ;
    USE SIGNAL ;
    SHAPE ABUTMENT ;
    PORT
      LAYER met2 ;
      RECT 696.370 0.000 696.510 0.420 ;
    END
  END r0_rd_out[24]
  PIN r0_rd_out[25]
    DIRECTION OUTPUT ;
    USE SIGNAL ;
    SHAPE ABUTMENT ;
    PORT
      LAYER met2 ;
      RECT 702.350 0.000 702.490 0.420 ;
    END
  END r0_rd_out[25]
  PIN r0_rd_out[26]
    DIRECTION OUTPUT ;
    USE SIGNAL ;
    SHAPE ABUTMENT ;
    PORT
      LAYER met2 ;
      RECT 708.330 0.000 708.470 0.420 ;
    END
  END r0_rd_out[26]
  PIN r0_rd_out[27]
    DIRECTION OUTPUT ;
    USE SIGNAL ;
    SHAPE ABUTMENT ;
    PORT
      LAYER met2 ;
      RECT 714.310 0.000 714.450 0.420 ;
    END
  END r0_rd_out[27]
  PIN r0_rd_out[28]
    DIRECTION OUTPUT ;
    USE SIGNAL ;
    SHAPE ABUTMENT ;
    PORT
      LAYER met2 ;
      RECT 720.290 0.000 720.430 0.420 ;
    END
  END r0_rd_out[28]
  PIN r0_rd_out[29]
    DIRECTION OUTPUT ;
    USE SIGNAL ;
    SHAPE ABUTMENT ;
    PORT
      LAYER met2 ;
      RECT 726.270 0.000 726.410 0.420 ;
    END
  END r0_rd_out[29]
  PIN r0_rd_out[30]
    DIRECTION OUTPUT ;
    USE SIGNAL ;
    SHAPE ABUTMENT ;
    PORT
      LAYER met2 ;
      RECT 732.250 0.000 732.390 0.420 ;
    END
  END r0_rd_out[30]
  PIN r0_rd_out[31]
    DIRECTION OUTPUT ;
    USE SIGNAL ;
    SHAPE ABUTMENT ;
    PORT
      LAYER met2 ;
      RECT 738.230 0.000 738.370 0.420 ;
    END
  END r0_rd_out[31]
  PIN r0_rd_out[32]
    DIRECTION OUTPUT ;
    USE SIGNAL ;
    SHAPE ABUTMENT ;
    PORT
      LAYER met2 ;
      RECT 744.210 0.000 744.350 0.420 ;
    END
  END r0_rd_out[32]
  PIN r0_rd_out[33]
    DIRECTION OUTPUT ;
    USE SIGNAL ;
    SHAPE ABUTMENT ;
    PORT
      LAYER met2 ;
      RECT 750.190 0.000 750.330 0.420 ;
    END
  END r0_rd_out[33]
  PIN r0_rd_out[34]
    DIRECTION OUTPUT ;
    USE SIGNAL ;
    SHAPE ABUTMENT ;
    PORT
      LAYER met2 ;
      RECT 756.170 0.000 756.310 0.420 ;
    END
  END r0_rd_out[34]
  PIN r0_rd_out[35]
    DIRECTION OUTPUT ;
    USE SIGNAL ;
    SHAPE ABUTMENT ;
    PORT
      LAYER met2 ;
      RECT 762.150 0.000 762.290 0.420 ;
    END
  END r0_rd_out[35]
  PIN r0_rd_out[36]
    DIRECTION OUTPUT ;
    USE SIGNAL ;
    SHAPE ABUTMENT ;
    PORT
      LAYER met2 ;
      RECT 768.130 0.000 768.270 0.420 ;
    END
  END r0_rd_out[36]
  PIN r0_rd_out[37]
    DIRECTION OUTPUT ;
    USE SIGNAL ;
    SHAPE ABUTMENT ;
    PORT
      LAYER met2 ;
      RECT 774.110 0.000 774.250 0.420 ;
    END
  END r0_rd_out[37]
  PIN r0_rd_out[38]
    DIRECTION OUTPUT ;
    USE SIGNAL ;
    SHAPE ABUTMENT ;
    PORT
      LAYER met2 ;
      RECT 780.090 0.000 780.230 0.420 ;
    END
  END r0_rd_out[38]
  PIN r0_rd_out[39]
    DIRECTION OUTPUT ;
    USE SIGNAL ;
    SHAPE ABUTMENT ;
    PORT
      LAYER met2 ;
      RECT 786.070 0.000 786.210 0.420 ;
    END
  END r0_rd_out[39]
  PIN r0_rd_out[40]
    DIRECTION OUTPUT ;
    USE SIGNAL ;
    SHAPE ABUTMENT ;
    PORT
      LAYER met2 ;
      RECT 792.050 0.000 792.190 0.420 ;
    END
  END r0_rd_out[40]
  PIN r0_rd_out[41]
    DIRECTION OUTPUT ;
    USE SIGNAL ;
    SHAPE ABUTMENT ;
    PORT
      LAYER met2 ;
      RECT 798.030 0.000 798.170 0.420 ;
    END
  END r0_rd_out[41]
  PIN r0_rd_out[42]
    DIRECTION OUTPUT ;
    USE SIGNAL ;
    SHAPE ABUTMENT ;
    PORT
      LAYER met2 ;
      RECT 804.010 0.000 804.150 0.420 ;
    END
  END r0_rd_out[42]
  PIN r0_rd_out[43]
    DIRECTION OUTPUT ;
    USE SIGNAL ;
    SHAPE ABUTMENT ;
    PORT
      LAYER met2 ;
      RECT 809.990 0.000 810.130 0.420 ;
    END
  END r0_rd_out[43]
  PIN r0_rd_out[44]
    DIRECTION OUTPUT ;
    USE SIGNAL ;
    SHAPE ABUTMENT ;
    PORT
      LAYER met2 ;
      RECT 815.970 0.000 816.110 0.420 ;
    END
  END r0_rd_out[44]
  PIN r0_rd_out[45]
    DIRECTION OUTPUT ;
    USE SIGNAL ;
    SHAPE ABUTMENT ;
    PORT
      LAYER met2 ;
      RECT 821.950 0.000 822.090 0.420 ;
    END
  END r0_rd_out[45]
  PIN r0_rd_out[46]
    DIRECTION OUTPUT ;
    USE SIGNAL ;
    SHAPE ABUTMENT ;
    PORT
      LAYER met2 ;
      RECT 383.570 948.860 383.710 949.280 ;
    END
  END r0_rd_out[46]
  PIN r0_rd_out[47]
    DIRECTION OUTPUT ;
    USE SIGNAL ;
    SHAPE ABUTMENT ;
    PORT
      LAYER met2 ;
      RECT 391.850 948.860 391.990 949.280 ;
    END
  END r0_rd_out[47]
  PIN r0_rd_out[48]
    DIRECTION OUTPUT ;
    USE SIGNAL ;
    SHAPE ABUTMENT ;
    PORT
      LAYER met2 ;
      RECT 400.130 948.860 400.270 949.280 ;
    END
  END r0_rd_out[48]
  PIN r0_rd_out[49]
    DIRECTION OUTPUT ;
    USE SIGNAL ;
    SHAPE ABUTMENT ;
    PORT
      LAYER met2 ;
      RECT 408.410 948.860 408.550 949.280 ;
    END
  END r0_rd_out[49]
  PIN r0_rd_out[50]
    DIRECTION OUTPUT ;
    USE SIGNAL ;
    SHAPE ABUTMENT ;
    PORT
      LAYER met2 ;
      RECT 416.690 948.860 416.830 949.280 ;
    END
  END r0_rd_out[50]
  PIN r0_rd_out[51]
    DIRECTION OUTPUT ;
    USE SIGNAL ;
    SHAPE ABUTMENT ;
    PORT
      LAYER met2 ;
      RECT 424.970 948.860 425.110 949.280 ;
    END
  END r0_rd_out[51]
  PIN r0_rd_out[52]
    DIRECTION OUTPUT ;
    USE SIGNAL ;
    SHAPE ABUTMENT ;
    PORT
      LAYER met2 ;
      RECT 433.250 948.860 433.390 949.280 ;
    END
  END r0_rd_out[52]
  PIN r0_rd_out[53]
    DIRECTION OUTPUT ;
    USE SIGNAL ;
    SHAPE ABUTMENT ;
    PORT
      LAYER met2 ;
      RECT 441.530 948.860 441.670 949.280 ;
    END
  END r0_rd_out[53]
  PIN r0_rd_out[54]
    DIRECTION OUTPUT ;
    USE SIGNAL ;
    SHAPE ABUTMENT ;
    PORT
      LAYER met2 ;
      RECT 449.810 948.860 449.950 949.280 ;
    END
  END r0_rd_out[54]
  PIN r0_rd_out[55]
    DIRECTION OUTPUT ;
    USE SIGNAL ;
    SHAPE ABUTMENT ;
    PORT
      LAYER met2 ;
      RECT 458.090 948.860 458.230 949.280 ;
    END
  END r0_rd_out[55]
  PIN r0_rd_out[56]
    DIRECTION OUTPUT ;
    USE SIGNAL ;
    SHAPE ABUTMENT ;
    PORT
      LAYER met2 ;
      RECT 466.370 948.860 466.510 949.280 ;
    END
  END r0_rd_out[56]
  PIN r0_rd_out[57]
    DIRECTION OUTPUT ;
    USE SIGNAL ;
    SHAPE ABUTMENT ;
    PORT
      LAYER met2 ;
      RECT 474.650 948.860 474.790 949.280 ;
    END
  END r0_rd_out[57]
  PIN r0_rd_out[58]
    DIRECTION OUTPUT ;
    USE SIGNAL ;
    SHAPE ABUTMENT ;
    PORT
      LAYER met2 ;
      RECT 482.930 948.860 483.070 949.280 ;
    END
  END r0_rd_out[58]
  PIN r0_rd_out[59]
    DIRECTION OUTPUT ;
    USE SIGNAL ;
    SHAPE ABUTMENT ;
    PORT
      LAYER met2 ;
      RECT 491.210 948.860 491.350 949.280 ;
    END
  END r0_rd_out[59]
  PIN r0_rd_out[60]
    DIRECTION OUTPUT ;
    USE SIGNAL ;
    SHAPE ABUTMENT ;
    PORT
      LAYER met2 ;
      RECT 499.490 948.860 499.630 949.280 ;
    END
  END r0_rd_out[60]
  PIN r0_rd_out[61]
    DIRECTION OUTPUT ;
    USE SIGNAL ;
    SHAPE ABUTMENT ;
    PORT
      LAYER met2 ;
      RECT 507.770 948.860 507.910 949.280 ;
    END
  END r0_rd_out[61]
  PIN r0_rd_out[62]
    DIRECTION OUTPUT ;
    USE SIGNAL ;
    SHAPE ABUTMENT ;
    PORT
      LAYER met2 ;
      RECT 516.050 948.860 516.190 949.280 ;
    END
  END r0_rd_out[62]
  PIN r0_rd_out[63]
    DIRECTION OUTPUT ;
    USE SIGNAL ;
    SHAPE ABUTMENT ;
    PORT
      LAYER met2 ;
      RECT 524.330 948.860 524.470 949.280 ;
    END
  END r0_rd_out[63]
  PIN r0_rd_out[64]
    DIRECTION OUTPUT ;
    USE SIGNAL ;
    SHAPE ABUTMENT ;
    PORT
      LAYER met2 ;
      RECT 532.610 948.860 532.750 949.280 ;
    END
  END r0_rd_out[64]
  PIN r0_rd_out[65]
    DIRECTION OUTPUT ;
    USE SIGNAL ;
    SHAPE ABUTMENT ;
    PORT
      LAYER met2 ;
      RECT 540.890 948.860 541.030 949.280 ;
    END
  END r0_rd_out[65]
  PIN r0_rd_out[66]
    DIRECTION OUTPUT ;
    USE SIGNAL ;
    SHAPE ABUTMENT ;
    PORT
      LAYER met2 ;
      RECT 549.170 948.860 549.310 949.280 ;
    END
  END r0_rd_out[66]
  PIN r0_rd_out[67]
    DIRECTION OUTPUT ;
    USE SIGNAL ;
    SHAPE ABUTMENT ;
    PORT
      LAYER met2 ;
      RECT 557.450 948.860 557.590 949.280 ;
    END
  END r0_rd_out[67]
  PIN r0_rd_out[68]
    DIRECTION OUTPUT ;
    USE SIGNAL ;
    SHAPE ABUTMENT ;
    PORT
      LAYER met2 ;
      RECT 565.730 948.860 565.870 949.280 ;
    END
  END r0_rd_out[68]
  PIN r0_rd_out[69]
    DIRECTION OUTPUT ;
    USE SIGNAL ;
    SHAPE ABUTMENT ;
    PORT
      LAYER met2 ;
      RECT 574.010 948.860 574.150 949.280 ;
    END
  END r0_rd_out[69]
  PIN r0_rd_out[70]
    DIRECTION OUTPUT ;
    USE SIGNAL ;
    SHAPE ABUTMENT ;
    PORT
      LAYER met2 ;
      RECT 582.290 948.860 582.430 949.280 ;
    END
  END r0_rd_out[70]
  PIN r0_rd_out[71]
    DIRECTION OUTPUT ;
    USE SIGNAL ;
    SHAPE ABUTMENT ;
    PORT
      LAYER met2 ;
      RECT 590.570 948.860 590.710 949.280 ;
    END
  END r0_rd_out[71]
  PIN r0_rd_out[72]
    DIRECTION OUTPUT ;
    USE SIGNAL ;
    SHAPE ABUTMENT ;
    PORT
      LAYER met2 ;
      RECT 598.850 948.860 598.990 949.280 ;
    END
  END r0_rd_out[72]
  PIN r0_rd_out[73]
    DIRECTION OUTPUT ;
    USE SIGNAL ;
    SHAPE ABUTMENT ;
    PORT
      LAYER met2 ;
      RECT 607.130 948.860 607.270 949.280 ;
    END
  END r0_rd_out[73]
  PIN r0_rd_out[74]
    DIRECTION OUTPUT ;
    USE SIGNAL ;
    SHAPE ABUTMENT ;
    PORT
      LAYER met2 ;
      RECT 615.410 948.860 615.550 949.280 ;
    END
  END r0_rd_out[74]
  PIN r0_rd_out[75]
    DIRECTION OUTPUT ;
    USE SIGNAL ;
    SHAPE ABUTMENT ;
    PORT
      LAYER met2 ;
      RECT 623.690 948.860 623.830 949.280 ;
    END
  END r0_rd_out[75]
  PIN r0_rd_out[76]
    DIRECTION OUTPUT ;
    USE SIGNAL ;
    SHAPE ABUTMENT ;
    PORT
      LAYER met2 ;
      RECT 631.970 948.860 632.110 949.280 ;
    END
  END r0_rd_out[76]
  PIN r0_rd_out[77]
    DIRECTION OUTPUT ;
    USE SIGNAL ;
    SHAPE ABUTMENT ;
    PORT
      LAYER met2 ;
      RECT 640.250 948.860 640.390 949.280 ;
    END
  END r0_rd_out[77]
  PIN r0_rd_out[78]
    DIRECTION OUTPUT ;
    USE SIGNAL ;
    SHAPE ABUTMENT ;
    PORT
      LAYER met2 ;
      RECT 648.530 948.860 648.670 949.280 ;
    END
  END r0_rd_out[78]
  PIN r0_rd_out[79]
    DIRECTION OUTPUT ;
    USE SIGNAL ;
    SHAPE ABUTMENT ;
    PORT
      LAYER met2 ;
      RECT 656.810 948.860 656.950 949.280 ;
    END
  END r0_rd_out[79]
  PIN r0_rd_out[80]
    DIRECTION OUTPUT ;
    USE SIGNAL ;
    SHAPE ABUTMENT ;
    PORT
      LAYER met2 ;
      RECT 665.090 948.860 665.230 949.280 ;
    END
  END r0_rd_out[80]
  PIN r0_rd_out[81]
    DIRECTION OUTPUT ;
    USE SIGNAL ;
    SHAPE ABUTMENT ;
    PORT
      LAYER met2 ;
      RECT 673.370 948.860 673.510 949.280 ;
    END
  END r0_rd_out[81]
  PIN r0_rd_out[82]
    DIRECTION OUTPUT ;
    USE SIGNAL ;
    SHAPE ABUTMENT ;
    PORT
      LAYER met2 ;
      RECT 681.650 948.860 681.790 949.280 ;
    END
  END r0_rd_out[82]
  PIN r0_rd_out[83]
    DIRECTION OUTPUT ;
    USE SIGNAL ;
    SHAPE ABUTMENT ;
    PORT
      LAYER met2 ;
      RECT 689.930 948.860 690.070 949.280 ;
    END
  END r0_rd_out[83]
  PIN r0_rd_out[84]
    DIRECTION OUTPUT ;
    USE SIGNAL ;
    SHAPE ABUTMENT ;
    PORT
      LAYER met2 ;
      RECT 698.210 948.860 698.350 949.280 ;
    END
  END r0_rd_out[84]
  PIN r0_rd_out[85]
    DIRECTION OUTPUT ;
    USE SIGNAL ;
    SHAPE ABUTMENT ;
    PORT
      LAYER met2 ;
      RECT 706.490 948.860 706.630 949.280 ;
    END
  END r0_rd_out[85]
  PIN r0_rd_out[86]
    DIRECTION OUTPUT ;
    USE SIGNAL ;
    SHAPE ABUTMENT ;
    PORT
      LAYER met2 ;
      RECT 714.770 948.860 714.910 949.280 ;
    END
  END r0_rd_out[86]
  PIN r0_rd_out[87]
    DIRECTION OUTPUT ;
    USE SIGNAL ;
    SHAPE ABUTMENT ;
    PORT
      LAYER met2 ;
      RECT 723.050 948.860 723.190 949.280 ;
    END
  END r0_rd_out[87]
  PIN r0_rd_out[88]
    DIRECTION OUTPUT ;
    USE SIGNAL ;
    SHAPE ABUTMENT ;
    PORT
      LAYER met2 ;
      RECT 731.330 948.860 731.470 949.280 ;
    END
  END r0_rd_out[88]
  PIN r0_rd_out[89]
    DIRECTION OUTPUT ;
    USE SIGNAL ;
    SHAPE ABUTMENT ;
    PORT
      LAYER met2 ;
      RECT 739.610 948.860 739.750 949.280 ;
    END
  END r0_rd_out[89]
  PIN r0_rd_out[90]
    DIRECTION OUTPUT ;
    USE SIGNAL ;
    SHAPE ABUTMENT ;
    PORT
      LAYER met2 ;
      RECT 747.890 948.860 748.030 949.280 ;
    END
  END r0_rd_out[90]
  PIN r0_rd_out[91]
    DIRECTION OUTPUT ;
    USE SIGNAL ;
    SHAPE ABUTMENT ;
    PORT
      LAYER met2 ;
      RECT 756.170 948.860 756.310 949.280 ;
    END
  END r0_rd_out[91]
  PIN rw0_addr_in[0]
    DIRECTION INPUT ;
    USE SIGNAL ;
    SHAPE ABUTMENT ;
    PORT
      LAYER met3 ;
      RECT 0.000 692.090 0.900 692.390 ;
    END
  END rw0_addr_in[0]
  PIN rw0_addr_in[1]
    DIRECTION INPUT ;
    USE SIGNAL ;
    SHAPE ABUTMENT ;
    PORT
      LAYER met3 ;
      RECT 0.000 722.010 0.900 722.310 ;
    END
  END rw0_addr_in[1]
  PIN rw0_addr_in[2]
    DIRECTION INPUT ;
    USE SIGNAL ;
    SHAPE ABUTMENT ;
    PORT
      LAYER met3 ;
      RECT 0.000 751.930 0.900 752.230 ;
    END
  END rw0_addr_in[2]
  PIN rw0_addr_in[3]
    DIRECTION INPUT ;
    USE SIGNAL ;
    SHAPE ABUTMENT ;
    PORT
      LAYER met3 ;
      RECT 0.000 781.850 0.900 782.150 ;
    END
  END rw0_addr_in[3]
  PIN rw0_addr_in[4]
    DIRECTION INPUT ;
    USE SIGNAL ;
    SHAPE ABUTMENT ;
    PORT
      LAYER met3 ;
      RECT 836.300 692.090 837.200 692.390 ;
    END
  END rw0_addr_in[4]
  PIN rw0_addr_in[5]
    DIRECTION INPUT ;
    USE SIGNAL ;
    SHAPE ABUTMENT ;
    PORT
      LAYER met3 ;
      RECT 836.300 722.010 837.200 722.310 ;
    END
  END rw0_addr_in[5]
  PIN rw0_addr_in[6]
    DIRECTION INPUT ;
    USE SIGNAL ;
    SHAPE ABUTMENT ;
    PORT
      LAYER met3 ;
      RECT 836.300 751.930 837.200 752.230 ;
    END
  END rw0_addr_in[6]
  PIN rw0_addr_in[7]
    DIRECTION INPUT ;
    USE SIGNAL ;
    SHAPE ABUTMENT ;
    PORT
      LAYER met3 ;
      RECT 836.300 781.850 837.200 782.150 ;
    END
  END rw0_addr_in[7]
  PIN r0_addr_in[0]
    DIRECTION INPUT ;
    USE SIGNAL ;
    SHAPE ABUTMENT ;
    PORT
      LAYER met3 ;
      RECT 0.000 811.770 0.900 812.070 ;
    END
  END r0_addr_in[0]
  PIN r0_addr_in[1]
    DIRECTION INPUT ;
    USE SIGNAL ;
    SHAPE ABUTMENT ;
    PORT
      LAYER met3 ;
      RECT 0.000 841.690 0.900 841.990 ;
    END
  END r0_addr_in[1]
  PIN r0_addr_in[2]
    DIRECTION INPUT ;
    USE SIGNAL ;
    SHAPE ABUTMENT ;
    PORT
      LAYER met3 ;
      RECT 0.000 871.610 0.900 871.910 ;
    END
  END r0_addr_in[2]
  PIN r0_addr_in[3]
    DIRECTION INPUT ;
    USE SIGNAL ;
    SHAPE ABUTMENT ;
    PORT
      LAYER met3 ;
      RECT 0.000 901.530 0.900 901.830 ;
    END
  END r0_addr_in[3]
  PIN r0_addr_in[4]
    DIRECTION INPUT ;
    USE SIGNAL ;
    SHAPE ABUTMENT ;
    PORT
      LAYER met3 ;
      RECT 836.300 811.770 837.200 812.070 ;
    END
  END r0_addr_in[4]
  PIN r0_addr_in[5]
    DIRECTION INPUT ;
    USE SIGNAL ;
    SHAPE ABUTMENT ;
    PORT
      LAYER met3 ;
      RECT 836.300 841.690 837.200 841.990 ;
    END
  END r0_addr_in[5]
  PIN r0_addr_in[6]
    DIRECTION INPUT ;
    USE SIGNAL ;
    SHAPE ABUTMENT ;
    PORT
      LAYER met3 ;
      RECT 836.300 871.610 837.200 871.910 ;
    END
  END r0_addr_in[6]
  PIN r0_addr_in[7]
    DIRECTION INPUT ;
    USE SIGNAL ;
    SHAPE ABUTMENT ;
    PORT
      LAYER met3 ;
      RECT 836.300 901.530 837.200 901.830 ;
    END
  END r0_addr_in[7]
  PIN rw0_we_in
    DIRECTION INPUT ;
    USE SIGNAL ;
    SHAPE ABUTMENT ;
    PORT
      LAYER met2 ;
      RECT 764.450 948.860 764.590 949.280 ;
    END
  END rw0_we_in
  PIN rw0_ce_in
    DIRECTION INPUT ;
    USE SIGNAL ;
    SHAPE ABUTMENT ;
    PORT
      LAYER met2 ;
      RECT 772.730 948.860 772.870 949.280 ;
    END
  END rw0_ce_in
  PIN rw0_clk
    DIRECTION INPUT ;
    USE SIGNAL ;
    SHAPE ABUTMENT ;
    PORT
      LAYER met2 ;
      RECT 781.010 948.860 781.150 949.280 ;
    END
  END rw0_clk
  PIN r0_ce_in
    DIRECTION INPUT ;
    USE SIGNAL ;
    SHAPE ABUTMENT ;
    PORT
      LAYER met2 ;
      RECT 789.290 948.860 789.430 949.280 ;
    END
  END r0_ce_in
  PIN r0_clk
    DIRECTION INPUT ;
    USE SIGNAL ;
    SHAPE ABUTMENT ;
    PORT
      LAYER met2 ;
      RECT 797.570 948.860 797.710 949.280 ;
    END
  END r0_clk
  PIN VSS
    DIRECTION INOUT ;
    USE GROUND ;
    PORT
      LAYER met4 ;
      RECT 2.160 4.080 3.360 945.200 ;
      RECT 13.040 4.080 14.240 945.200 ;
      RECT 23.920 4.080 25.120 945.200 ;
      RECT 34.800 4.080 36.000 945.200 ;
      RECT 45.680 4.080 46.880 945.200 ;
      RECT 56.560 4.080 57.760 945.200 ;
      RECT 67.440 4.080 68.640 945.200 ;
      RECT 78.320 4.080 79.520 945.200 ;
      RECT 89.200 4.080 90.400 945.200 ;
      RECT 100.080 4.080 101.280 945.200 ;
      RECT 110.960 4.080 112.160 945.200 ;
      RECT 121.840 4.080 123.040 945.200 ;
      RECT 132.720 4.080 133.920 945.200 ;
      RECT 143.600 4.080 144.800 945.200 ;
      RECT 154.480 4.080 155.680 945.200 ;
      RECT 165.360 4.080 166.560 945.200 ;
      RECT 176.240 4.080 177.440 945.200 ;
      RECT 187.120 4.080 188.320 945.200 ;
      RECT 198.000 4.080 199.200 945.200 ;
      RECT 208.880 4.080 210.080 945.200 ;
      RECT 219.760 4.080 220.960 945.200 ;
      RECT 230.640 4.080 231.840 945.200 ;
      RECT 241.520 4.080 242.720 945.200 ;
      RECT 252.400 4.080 253.600 945.200 ;
      RECT 263.280 4.080 264.480 945.200 ;
      RECT 274.160 4.080 275.360 945.200 ;
      RECT 285.040 4.080 286.240 945.200 ;
      RECT 295.920 4.080 297.120 945.200 ;
      RECT 306.800 4.080 308.000 945.200 ;
      RECT 317.680 4.080 318.880 945.200 ;
      RECT 328.560 4.080 329.760 945.200 ;
      RECT 339.440 4.080 340.640 945.200 ;
      RECT 350.320 4.080 351.520 945.200 ;
      RECT 361.200 4.080 362.400 945.200 ;
      RECT 372.080 4.080 373.280 945.200 ;
      RECT 382.960 4.080 384.160 945.200 ;
      RECT 393.840 4.080 395.040 945.200 ;
      RECT 404.720 4.080 405.920 945.200 ;
      RECT 415.600 4.080 416.800 945.200 ;
      RECT 426.480 4.080 427.680 945.200 ;
      RECT 437.360 4.080 438.560 945.200 ;
      RECT 448.240 4.080 449.440 945.200 ;
      RECT 459.120 4.080 460.320 945.200 ;
      RECT 470.000 4.080 471.200 945.200 ;
      RECT 480.880 4.080 482.080 945.200 ;
      RECT 491.760 4.080 492.960 945.200 ;
      RECT 502.640 4.080 503.840 945.200 ;
      RECT 513.520 4.080 514.720 945.200 ;
      RECT 524.400 4.080 525.600 945.200 ;
      RECT 535.280 4.080 536.480 945.200 ;
      RECT 546.160 4.080 547.360 945.200 ;
      RECT 557.040 4.080 558.240 945.200 ;
      RECT 567.920 4.080 569.120 945.200 ;
      RECT 578.800 4.080 580.000 945.200 ;
      RECT 589.680 4.080 590.880 945.200 ;
      RECT 600.560 4.080 601.760 945.200 ;
      RECT 611.440 4.080 612.640 945.200 ;
      RECT 622.320 4.080 623.520 945.200 ;
      RECT 633.200 4.080 634.400 945.200 ;
      RECT 644.080 4.080 645.280 945.200 ;
      RECT 654.960 4.080 656.160 945.200 ;
      RECT 665.840 4.080 667.040 945.200 ;
      RECT 676.720 4.080 677.920 945.200 ;
      RECT 687.600 4.080 688.800 945.200 ;
      RECT 698.480 4.080 699.680 945.200 ;
      RECT 709.360 4.080 710.560 945.200 ;
      RECT 720.240 4.080 721.440 945.200 ;
      RECT 731.120 4.080 732.320 945.200 ;
      RECT 742.000 4.080 743.200 945.200 ;
      RECT 752.880 4.080 754.080 945.200 ;
      RECT 763.760 4.080 764.960 945.200 ;
      RECT 774.640 4.080 775.840 945.200 ;
      RECT 785.520 4.080 786.720 945.200 ;
      RECT 796.400 4.080 797.600 945.200 ;
      RECT 807.280 4.080 808.480 945.200 ;
      RECT 818.160 4.080 819.360 945.200 ;
      RECT 829.040 4.080 830.240 945.200 ;
    END
  END VSS
  PIN VDD
    DIRECTION INOUT ;
    USE POWER ;
    PORT
      LAYER met4 ;
      RECT 7.600 4.080 8.800 945.200 ;
      RECT 18.480 4.080 19.680 945.200 ;
      RECT 29.360 4.080 30.560 945.200 ;
      RECT 40.240 4.080 41.440 945.200 ;
      RECT 51.120 4.080 52.320 945.200 ;
      RECT 62.000 4.080 63.200 945.200 ;
      RECT 72.880 4.080 74.080 945.200 ;
      RECT 83.760 4.080 84.960 945.200 ;
      RECT 94.640 4.080 95.840 945.200 ;
      RECT 105.520 4.080 106.720 945.200 ;
      RECT 116.400 4.080 117.600 945.200 ;
      RECT 127.280 4.080 128.480 945.200 ;
      RECT 138.160 4.080 139.360 945.200 ;
      RECT 149.040 4.080 150.240 945.200 ;
      RECT 159.920 4.080 161.120 945.200 ;
      RECT 170.800 4.080 172.000 945.200 ;
      RECT 181.680 4.080 182.880 945.200 ;
      RECT 192.560 4.080 193.760 945.200 ;
      RECT 203.440 4.080 204.640 945.200 ;
      RECT 214.320 4.080 215.520 945.200 ;
      RECT 225.200 4.080 226.400 945.200 ;
      RECT 236.080 4.080 237.280 945.200 ;
      RECT 246.960 4.080 248.160 945.200 ;
      RECT 257.840 4.080 259.040 945.200 ;
      RECT 268.720 4.080 269.920 945.200 ;
      RECT 279.600 4.080 280.800 945.200 ;
      RECT 290.480 4.080 291.680 945.200 ;
      RECT 301.360 4.080 302.560 945.200 ;
      RECT 312.240 4.080 313.440 945.200 ;
      RECT 323.120 4.080 324.320 945.200 ;
      RECT 334.000 4.080 335.200 945.200 ;
      RECT 344.880 4.080 346.080 945.200 ;
      RECT 355.760 4.080 356.960 945.200 ;
      RECT 366.640 4.080 367.840 945.200 ;
      RECT 377.520 4.080 378.720 945.200 ;
      RECT 388.400 4.080 389.600 945.200 ;
      RECT 399.280 4.080 400.480 945.200 ;
      RECT 410.160 4.080 411.360 945.200 ;
      RECT 421.040 4.080 422.240 945.200 ;
      RECT 431.920 4.080 433.120 945.200 ;
      RECT 442.800 4.080 444.000 945.200 ;
      RECT 453.680 4.080 454.880 945.200 ;
      RECT 464.560 4.080 465.760 945.200 ;
      RECT 475.440 4.080 476.640 945.200 ;
      RECT 486.320 4.080 487.520 945.200 ;
      RECT 497.200 4.080 498.400 945.200 ;
      RECT 508.080 4.080 509.280 945.200 ;
      RECT 518.960 4.080 520.160 945.200 ;
      RECT 529.840 4.080 531.040 945.200 ;
      RECT 540.720 4.080 541.920 945.200 ;
      RECT 551.600 4.080 552.800 945.200 ;
      RECT 562.480 4.080 563.680 945.200 ;
      RECT 573.360 4.080 574.560 945.200 ;
      RECT 584.240 4.080 585.440 945.200 ;
      RECT 595.120 4.080 596.320 945.200 ;
      RECT 606.000 4.080 607.200 945.200 ;
      RECT 616.880 4.080 618.080 945.200 ;
      RECT 627.760 4.080 628.960 945.200 ;
      RECT 638.640 4.080 639.840 945.200 ;
      RECT 649.520 4.080 650.720 945.200 ;
      RECT 660.400 4.080 661.600 945.200 ;
      RECT 671.280 4.080 672.480 945.200 ;
      RECT 682.160 4.080 683.360 945.200 ;
      RECT 693.040 4.080 694.240 945.200 ;
      RECT 703.920 4.080 705.120 945.200 ;
      RECT 714.800 4.080 716.000 945.200 ;
      RECT 725.680 4.080 726.880 945.200 ;
      RECT 736.560 4.080 737.760 945.200 ;
      RECT 747.440 4.080 748.640 945.200 ;
      RECT 758.320 4.080 759.520 945.200 ;
      RECT 769.200 4.080 770.400 945.200 ;
      RECT 780.080 4.080 781.280 945.200 ;
      RECT 790.960 4.080 792.160 945.200 ;
      RECT 801.840 4.080 803.040 945.200 ;
      RECT 812.720 4.080 813.920 945.200 ;
      RECT 823.600 4.080 824.800 945.200 ;
      RECT 834.480 4.080 835.680 945.200 ;
    END
  END VDD
  OBS
    LAYER met1 ;
    RECT 0 0 837.200 949.280 ;
    LAYER met2 ;
    RECT 0 0 837.200 949.280 ;
    LAYER met3 ;
    RECT 0 0 837.200 949.280 ;
    LAYER met4 ;
    RECT 0 0 837.200 949.280 ;
  END
END fakeram_1rw1r_92w256d_sram

END LIBRARY
